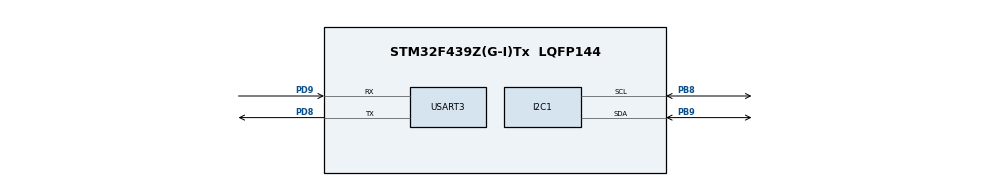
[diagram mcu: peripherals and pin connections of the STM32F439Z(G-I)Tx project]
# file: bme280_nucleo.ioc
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Mcu.Family=STM32F4
Mcu.Name=STM32F439Z(G-I)Tx
Mcu.Package=LQFP144
NVIC.PriorityGroup=NVIC_PRIORITYGROUP_4
PD8.Mode=Asynchronous
PD8.Signal=USART3_TX
PD9.Mode=Asynchronous
PD9.Signal=USART3_RX
PB8.GPIO_Pu=GPIO_PULLUP
PB8.Mode=I2C
PB8.Signal=I2C1_SCL
PB9.Mode=I2C
PB9.Signal=I2C1_SDA
ProjectManager.HeapSize=0x200
ProjectManager.StackSize=0x400
ProjectManager.TargetToolchain=Makefile
RCC.48MHZClocksFreq_Value=14285714.285714285
RCC.AHBFreq_Value=50000000
RCC.APB1CLKDivider=RCC_HCLK_DIV4
RCC.APB1Freq_Value=12500000
RCC.APB1TimFreq_Value=25000000
RCC.APB2CLKDivider=RCC_HCLK_DIV4
RCC.APB2Freq_Value=12500000
RCC.APB2TimCLKDivider=2
RCC.APB2TimFreq_Value=25000000
RCC.CortexFreq_Value=50000000
RCC.HCLKFreq_Value=50000000
RCC.HSE_VALUE=8000000
RCC.HSI_VALUE=16000000
RCC.PLLM=8
RCC.PLLMUL=RCC_PLL_MUL9
RCC.PLLN=50
RCC.PLLQ=7
RCC.PRESCALERUSB=RCC_USBCLKSOURCE_PLL_DIV1_5
RCC.SYSCLKFreq_VALUE=50000000
RCC.SYSCLKSource=RCC_SYSCLKSOURCE_PLLCLK
RCC.SYSCLKSourceVirtual=RCC_SYSCLKSOURCE_PLLCLK
RCC.USBFreq_Value=48000000
RCC.VCOOutputFreq_Value=100000000
USART3.VirtualMode=VM_ASYNC
board=NUCLEO-F439ZI

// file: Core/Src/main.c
/* USER CODE BEGIN Header */
/**
  ******************************************************************************
  * @file           : main.c
  * @brief          : Main program body
  ******************************************************************************
  * @attention
  *
  * Copyright (c) 2025 STMicroelectronics.
  * All rights reserved.
  *
  * This software is licensed under terms that can be found in the LICENSE file
  * in the root directory of this software component.
  * If no LICENSE file comes with this software, it is provided AS-IS.
  *
  ******************************************************************************
  */
/* USER CODE END Header */
#include "main.h"
#include "i2c.h"
#include "usart.h"
#include "gpio.h"

/* USER CODE BEGIN Includes */
#include "bme280.h"
#include <stdio.h>
#include <string.h>
/* USER CODE END Includes */

/* USER CODE BEGIN PV */
static BME280_Handle_t bme280;
static BME280_Measurement_t bme280_meas;
static char line[96];
/* USER CODE END PV */

void SystemClock_Config(void);

int main(void)
{

  /* MCU Configuration--------------------------------------------------------*/

  /* Reset of all peripherals, Initializes the Flash interface and the Systick. */
  HAL_Init();

  /* Configure the system clock */
  SystemClock_Config();

  /* Initialize all configured peripherals */
  MX_GPIO_Init();
  MX_I2C1_Init();
  MX_USART3_UART_Init();
  /* USER CODE BEGIN 2 */
  const char *uart_ping = "USART3 online\r\n";
  HAL_UART_Transmit(&huart3, (uint8_t *)uart_ping, strlen(uart_ping), HAL_MAX_DELAY);

  bme280.i2c = &hi2c1;
  bme280.address = BME280_I2C_ADDR_DEFAULT;

  if (BME280_Init(&bme280) != HAL_OK)
  {
    const char *msg = "BME280 init failed\r\n";
    HAL_UART_Transmit(&huart3, (uint8_t *)msg, strlen(msg), HAL_MAX_DELAY);
    Error_Handler();
  }

  const char *banner = "BME280 ready. Reading measurements...\r\n";
  HAL_UART_Transmit(&huart3, (uint8_t *)banner, strlen(banner), HAL_MAX_DELAY);
  /* USER CODE END 2 */

  /* Infinite loop */
  while (1)
  {

    /* USER CODE BEGIN 3 */
    if (BME280_ReadMeasurements(&bme280, &bme280_meas) == HAL_OK)
    {
      int len = snprintf(line, sizeof(line),
                         "Temp: %.2f C, Humidity: %.2f %%RH, Pressure: %.2f hPa\r\n",
                         bme280_meas.temperature_c,
                         bme280_meas.humidity_rh,
                         bme280_meas.pressure_pa / 100.0f);
      if (len > 0)
      {
        HAL_UART_Transmit(&huart3, (uint8_t *)line, (uint16_t)len, HAL_MAX_DELAY);
      }
    }
    else
    {
      const char *err = "BME280 read error\r\n";
      HAL_UART_Transmit(&huart3, (uint8_t *)err, strlen(err), HAL_MAX_DELAY);
    }

    HAL_Delay(1000);
  }
  /* USER CODE END 3 */
}

void SystemClock_Config(void)
{
  RCC_OscInitTypeDef RCC_OscInitStruct = {0};
  RCC_ClkInitTypeDef RCC_ClkInitStruct = {0};

  __HAL_RCC_PWR_CLK_ENABLE();
  __HAL_PWR_VOLTAGESCALING_CONFIG(PWR_REGULATOR_VOLTAGE_SCALE1);

  RCC_OscInitStruct.OscillatorType = RCC_OSCILLATORTYPE_HSE;
  RCC_OscInitStruct.HSEState = RCC_HSE_ON;
  RCC_OscInitStruct.PLL.PLLState = RCC_PLL_ON;
  RCC_OscInitStruct.PLL.PLLSource = RCC_PLLSOURCE_HSE;
  RCC_OscInitStruct.PLL.PLLM = 8;
  RCC_OscInitStruct.PLL.PLLN = 360;
  RCC_OscInitStruct.PLL.PLLP = RCC_PLLP_DIV2;
  RCC_OscInitStruct.PLL.PLLQ = 7;
  if (HAL_RCC_OscConfig(&RCC_OscInitStruct) != HAL_OK)
  {
    Error_Handler();
  }

  if (HAL_PWREx_EnableOverDrive() != HAL_OK)
  {
    Error_Handler();
  }

  RCC_ClkInitStruct.ClockType = RCC_CLOCKTYPE_HCLK | RCC_CLOCKTYPE_SYSCLK |
                                RCC_CLOCKTYPE_PCLK1 | RCC_CLOCKTYPE_PCLK2;
  RCC_ClkInitStruct.SYSCLKSource = RCC_SYSCLKSOURCE_PLLCLK;
  RCC_ClkInitStruct.AHBCLKDivider = RCC_SYSCLK_DIV1;
  RCC_ClkInitStruct.APB1CLKDivider = RCC_HCLK_DIV4;
  RCC_ClkInitStruct.APB2CLKDivider = RCC_HCLK_DIV2;

  if (HAL_RCC_ClockConfig(&RCC_ClkInitStruct, FLASH_LATENCY_5) != HAL_OK)
  {
    Error_Handler();
  }
}

void Error_Handler(void)
{
  __disable_irq();
  while (1)
  {
  }
}
